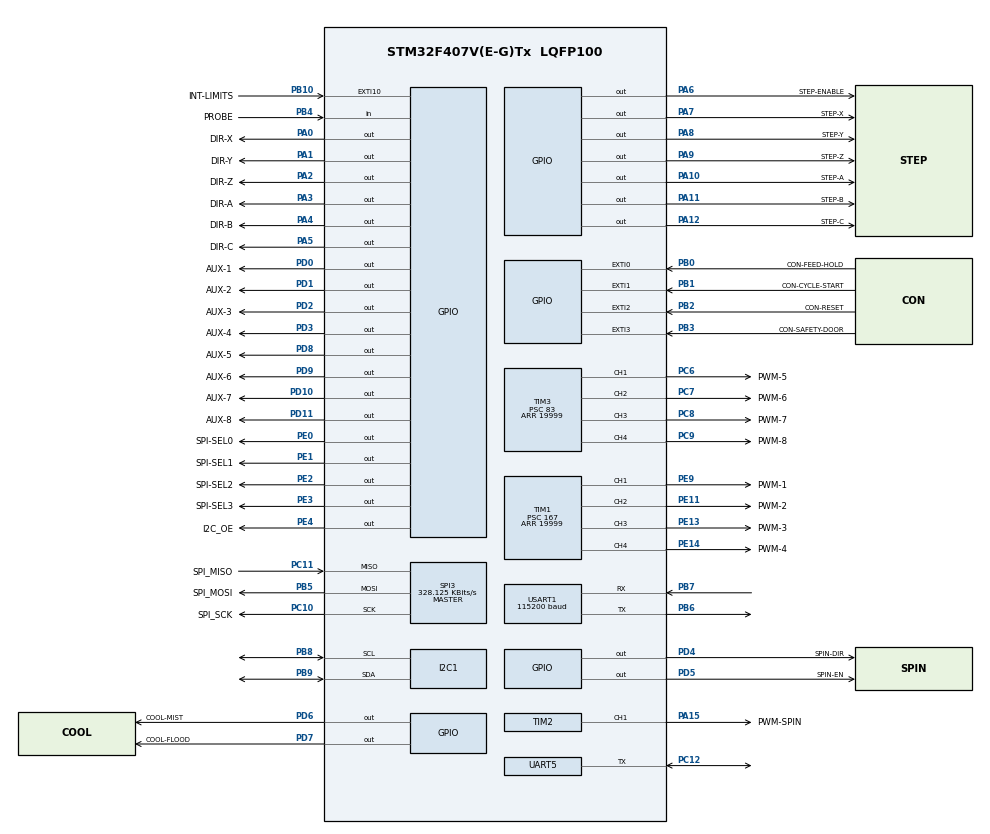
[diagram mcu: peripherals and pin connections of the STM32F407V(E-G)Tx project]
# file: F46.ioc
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Mcu.Family=STM32F4
Mcu.Name=STM32F407V(E-G)Tx
Mcu.Package=LQFP100
NVIC.EXTI0_IRQn=true\:0\:0\:false\:true\:true\:2\:true\:true\:true
NVIC.EXTI15_10_IRQn=true\:0\:0\:false\:false\:true\:true\:true\:true
NVIC.EXTI1_IRQn=true\:0\:0\:false\:true\:true\:3\:true\:true\:true
NVIC.EXTI2_IRQn=true\:0\:0\:false\:true\:true\:4\:true\:true\:true
NVIC.EXTI3_IRQn=true\:0\:0\:false\:true\:true\:5\:true\:true\:true
NVIC.PriorityGroup=NVIC_PRIORITYGROUP_4
NVIC.TIM5_IRQn=true\:0\:0\:false\:false\:true\:true\:true\:true
NVIC.TIM7_IRQn=true\:0\:0\:false\:false\:true\:true\:true\:true
NVIC.USART1_IRQn=true\:0\:0\:false\:true\:true\:1\:true\:true\:true
PA0-WKUP.GPIO_Label=DIR-X
PA0-WKUP.GPIO_ModeDefaultOutputPP=GPIO_MODE_OUTPUT_PP
PA0-WKUP.GPIO_Speed=GPIO_SPEED_FREQ_VERY_HIGH
PA0-WKUP.Signal=GPIO_Output
PA1.GPIO_Label=DIR-Y
PA1.GPIO_ModeDefaultOutputPP=GPIO_MODE_OUTPUT_PP
PA1.GPIO_Speed=GPIO_SPEED_FREQ_VERY_HIGH
PA1.Signal=GPIO_Output
PA10.GPIO_Label=STEP-A
PA10.GPIO_ModeDefaultOutputPP=GPIO_MODE_OUTPUT_PP
PA10.GPIO_Speed=GPIO_SPEED_FREQ_VERY_HIGH
PA10.Signal=GPIO_Output
PA11.GPIO_Label=STEP-B
PA11.GPIO_ModeDefaultOutputPP=GPIO_MODE_OUTPUT_PP
PA11.GPIO_Speed=GPIO_SPEED_FREQ_VERY_HIGH
PA11.Signal=GPIO_Output
PA12.GPIO_Label=STEP-C
PA12.GPIO_ModeDefaultOutputPP=GPIO_MODE_OUTPUT_PP
PA12.GPIO_Speed=GPIO_SPEED_FREQ_VERY_HIGH
PA12.Signal=GPIO_Output
PA13.Mode=Serial_Wire
PA13.Signal=SYS_JTMS-SWDIO
PA14.Mode=Serial_Wire
PA14.Signal=SYS_JTCK-SWCLK
PA15.GPIO_Label=PWM-SPIN
PA15.Signal=S_TIM2_CH1_ETR
PA2.GPIO_Label=DIR-Z
PA2.GPIO_ModeDefaultOutputPP=GPIO_MODE_OUTPUT_PP
PA2.GPIO_Speed=GPIO_SPEED_FREQ_VERY_HIGH
PA2.Signal=GPIO_Output
PA3.GPIO_Label=DIR-A
PA3.GPIO_ModeDefaultOutputPP=GPIO_MODE_OUTPUT_PP
PA3.GPIO_Speed=GPIO_SPEED_FREQ_VERY_HIGH
PA3.Signal=GPIO_Output
PA4.GPIO_Label=DIR-B
PA4.GPIO_ModeDefaultOutputPP=GPIO_MODE_OUTPUT_PP
PA4.GPIO_Speed=GPIO_SPEED_FREQ_VERY_HIGH
PA4.Signal=GPIO_Output
PA5.GPIO_Label=DIR-C
PA5.GPIO_ModeDefaultOutputPP=GPIO_MODE_OUTPUT_PP
PA5.GPIO_Speed=GPIO_SPEED_FREQ_VERY_HIGH
PA5.Signal=GPIO_Output
PA6.GPIO_Label=STEP-ENABLE
PA6.GPIO_ModeDefaultOutputPP=GPIO_MODE_OUTPUT_PP
PA6.GPIO_Speed=GPIO_SPEED_FREQ_VERY_HIGH
PA6.Signal=GPIO_Output
PA7.GPIO_Label=STEP-X
PA7.GPIO_ModeDefaultOutputPP=GPIO_MODE_OUTPUT_PP
PA7.GPIO_Speed=GPIO_SPEED_FREQ_VERY_HIGH
PA7.Signal=GPIO_Output
PA8.GPIO_Label=STEP-Y
PA8.GPIO_ModeDefaultOutputPP=GPIO_MODE_OUTPUT_PP
PA8.GPIO_Speed=GPIO_SPEED_FREQ_VERY_HIGH
PA8.Signal=GPIO_Output
PA9.GPIO_Label=STEP-Z
PA9.GPIO_ModeDefaultOutputPP=GPIO_MODE_OUTPUT_PP
PA9.GPIO_Speed=GPIO_SPEED_FREQ_VERY_HIGH
PA9.Signal=GPIO_Output
PB0.GPIO_Label=CON-FEED-HOLD
PB0.GPIO_ModeDefaultEXTI=GPIO_MODE_IT_FALLING
PB0.GPIO_PuPd=GPIO_PULLUP
PB0.Signal=GPXTI0
PB1.GPIO_Label=CON-CYCLE-START
PB1.GPIO_ModeDefaultEXTI=GPIO_MODE_IT_FALLING
PB1.GPIO_PuPd=GPIO_PULLUP
PB1.Signal=GPXTI1
PB10.GPIO_Label=INT-LIMITS
PB10.GPIO_ModeDefaultEXTI=GPIO_MODE_IT_FALLING
PB10.GPIO_PuPd=GPIO_PULLUP
PB10.Signal=GPXTI10
PB2.GPIO_Label=CON-RESET
PB2.GPIO_ModeDefaultEXTI=GPIO_MODE_IT_FALLING
PB2.GPIO_PuPd=GPIO_PULLUP
PB2.Signal=GPXTI2
PB3.GPIO_Label=CON-SAFETY-DOOR
PB3.GPIO_ModeDefaultEXTI=GPIO_MODE_IT_FALLING
PB3.GPIO_PuPd=GPIO_PULLUP
PB3.Signal=GPXTI3
PB4.GPIO_Label=PROBE
PB4.GPIO_PuPd=GPIO_PULLUP
PB4.Signal=GPIO_Input
PB5.GPIO_Label=SPI_MOSI
PB5.Mode=Full_Duplex_Master
PB5.Signal=SPI3_MOSI
PB6.Mode=Asynchronous
PB6.Signal=USART1_TX
PB7.Mode=Asynchronous
PB7.Signal=USART1_RX
PB8.GPIO_Pu=GPIO_PULLUP
PB8.Mode=I2C
PB8.Signal=I2C1_SCL
PB9.GPIO_Pu=GPIO_PULLUP
PB9.Mode=I2C
PB9.Signal=I2C1_SDA
PC10.GPIO_Label=SPI_SCK
PC10.Mode=Full_Duplex_Master
PC10.Signal=SPI3_SCK
PC11.GPIO_Label=SPI_MISO
PC11.Mode=Full_Duplex_Master
PC11.Signal=SPI3_MISO
PC12.Mode=Half_duplex(single_wire_mode)
PC12.Signal=UART5_TX
PC6.GPIO_Label=PWM-5
PC6.Signal=S_TIM3_CH1
PC7.GPIO_Label=PWM-6
PC7.Signal=S_TIM3_CH2
PC8.GPIO_Label=PWM-7
PC8.Signal=S_TIM3_CH3
PC9.GPIO_Label=PWM-8
PC9.Signal=S_TIM3_CH4
PD0.GPIO_Label=AUX-1
PD0.GPIO_ModeDefaultOutputPP=GPIO_MODE_OUTPUT_PP
PD0.GPIO_PuPd=GPIO_NOPULL
PD0.GPIO_Speed=GPIO_SPEED_FREQ_VERY_HIGH
PD0.PinState=GPIO_PIN_RESET
PD0.Signal=GPIO_Output
PD1.GPIO_Label=AUX-2
PD1.GPIO_ModeDefaultOutputPP=GPIO_MODE_OUTPUT_PP
PD1.GPIO_PuPd=GPIO_NOPULL
PD1.GPIO_Speed=GPIO_SPEED_FREQ_VERY_HIGH
PD1.PinState=GPIO_PIN_RESET
PD1.Signal=GPIO_Output
PD10.GPIO_Label=AUX-7
PD10.GPIO_ModeDefaultOutputPP=GPIO_MODE_OUTPUT_PP
PD10.GPIO_PuPd=GPIO_NOPULL
PD10.GPIO_Speed=GPIO_SPEED_FREQ_VERY_HIGH
PD10.PinState=GPIO_PIN_RESET
PD10.Signal=GPIO_Output
PD11.GPIO_Label=AUX-8
PD11.GPIO_ModeDefaultOutputPP=GPIO_MODE_OUTPUT_PP
PD11.GPIO_PuPd=GPIO_NOPULL
PD11.GPIO_Speed=GPIO_SPEED_FREQ_VERY_HIGH
PD11.PinState=GPIO_PIN_RESET
PD11.Signal=GPIO_Output
PD2.GPIO_Label=AUX-3
PD2.GPIO_Speed=GPIO_SPEED_FREQ_VERY_HIGH
PD2.Signal=GPIO_Output
PD3.GPIO_Label=AUX-4
PD3.GPIO_ModeDefaultOutputPP=GPIO_MODE_OUTPUT_PP
PD3.GPIO_PuPd=GPIO_NOPULL
PD3.GPIO_Speed=GPIO_SPEED_FREQ_VERY_HIGH
PD3.PinState=GPIO_PIN_RESET
PD3.Signal=GPIO_Output
PD4.GPIO_Label=SPIN-DIR
PD4.GPIO_ModeDefaultOutputPP=GPIO_MODE_OUTPUT_PP
PD4.GPIO_PuPd=GPIO_NOPULL
PD4.GPIO_Speed=GPIO_SPEED_FREQ_VERY_HIGH
PD4.PinState=GPIO_PIN_RESET
PD4.Signal=GPIO_Output
PD5.GPIO_Label=SPIN-EN
PD5.GPIO_ModeDefaultOutputPP=GPIO_MODE_OUTPUT_PP
PD5.GPIO_PuPd=GPIO_NOPULL
PD5.GPIO_Speed=GPIO_SPEED_FREQ_VERY_HIGH
PD5.PinState=GPIO_PIN_RESET
PD5.Signal=GPIO_Output
PD6.GPIO_Label=COOL-MIST
PD6.GPIO_ModeDefaultOutputPP=GPIO_MODE_OUTPUT_PP
PD6.GPIO_PuPd=GPIO_NOPULL
PD6.GPIO_Speed=GPIO_SPEED_FREQ_VERY_HIGH
PD6.PinState=GPIO_PIN_RESET
PD6.Signal=GPIO_Output
PD7.GPIO_Label=COOL-FLOOD
PD7.GPIO_ModeDefaultOutputPP=GPIO_MODE_OUTPUT_PP
PD7.GPIO_PuPd=GPIO_NOPULL
PD7.GPIO_Speed=GPIO_SPEED_FREQ_VERY_HIGH
PD7.PinState=GPIO_PIN_RESET
PD7.Signal=GPIO_Output
PD8.GPIO_Label=AUX-5
PD8.GPIO_ModeDefaultOutputPP=GPIO_MODE_OUTPUT_PP
PD8.GPIO_PuPd=GPIO_NOPULL
PD8.GPIO_Speed=GPIO_SPEED_FREQ_VERY_HIGH
PD8.PinState=GPIO_PIN_RESET
PD8.Signal=GPIO_Output
PD9.GPIO_Label=AUX-6
PD9.GPIO_ModeDefaultOutputPP=GPIO_MODE_OUTPUT_PP
PD9.GPIO_PuPd=GPIO_NOPULL
PD9.GPIO_Speed=GPIO_SPEED_FREQ_VERY_HIGH
PD9.PinState=GPIO_PIN_RESET
PD9.Signal=GPIO_Output
PE0.GPIO_Label=SPI-SEL0
PE0.GPIO_Speed=GPIO_SPEED_FREQ_VERY_HIGH
PE0.Signal=GPIO_Output
PE1.GPIO_Label=SPI-SEL1
PE1.GPIO_Speed=GPIO_SPEED_FREQ_VERY_HIGH
PE1.Signal=GPIO_Output
PE11.GPIO_Label=PWM-2
PE11.Signal=S_TIM1_CH2
PE13.GPIO_Label=PWM-3
PE13.Signal=S_TIM1_CH3
PE14.GPIO_Label=PWM-4
PE14.Signal=S_TIM1_CH4
PE2.GPIO_Label=SPI-SEL2
PE2.GPIO_Speed=GPIO_SPEED_FREQ_VERY_HIGH
PE2.Signal=GPIO_Output
PE3.GPIO_Label=SPI-SEL3
PE3.GPIO_Speed=GPIO_SPEED_FREQ_VERY_HIGH
PE3.Signal=GPIO_Output
PE4.GPIO_Label=I2C_OE
PE4.Signal=GPIO_Output
PE9.GPIO_Label=PWM-1
PE9.Signal=S_TIM1_CH1
PH0-OSC_IN.Mode=HSE-External-Oscillator
PH0-OSC_IN.Signal=RCC_OSC_IN
PH1-OSC_OUT.Mode=HSE-External-Oscillator
PH1-OSC_OUT.Signal=RCC_OSC_OUT
ProjectManager.HeapSize=0x200
ProjectManager.StackSize=0x400
ProjectManager.TargetToolchain=MDK-ARM V5.32
RCC.48MHZClocksFreq_Value=84000000
RCC.AHBFreq_Value=168000000
RCC.APB1CLKDivider=RCC_HCLK_DIV4
RCC.APB1Freq_Value=42000000
RCC.APB1TimFreq_Value=84000000
RCC.APB2CLKDivider=RCC_HCLK_DIV2
RCC.APB2Freq_Value=84000000
RCC.APB2TimFreq_Value=168000000
RCC.CortexFreq_Value=168000000
RCC.FLatency=FLASH_LATENCY_5
RCC.HCLKFreq_Value=168000000
RCC.HSE_VALUE=8000000
RCC.HSI_VALUE=16000000
RCC.LSE_VALUE=32768
RCC.PLLM=8
RCC.PLLN=168
RCC.SYSCLKFreq_VALUE=168000000
RCC.SYSCLKSource=RCC_SYSCLKSOURCE_PLLCLK
RCC.VCOOutputFreq_Value=336000000
SH.S_TIM1_CH1.0=TIM1_CH1,PWM Generation1 CH1
SH.S_TIM1_CH2.0=TIM1_CH2,PWM Generation2 CH2
SH.S_TIM1_CH3.0=TIM1_CH3,PWM Generation3 CH3
SH.S_TIM1_CH4.0=TIM1_CH4,PWM Generation4 CH4
SH.S_TIM2_CH1_ETR.0=TIM2_CH1,PWM Generation1 CH1
SH.S_TIM3_CH1.0=TIM3_CH1,PWM Generation1 CH1
SH.S_TIM3_CH2.0=TIM3_CH2,PWM Generation2 CH2
SH.S_TIM3_CH3.0=TIM3_CH3,PWM Generation3 CH3
SH.S_TIM3_CH4.0=TIM3_CH4,PWM Generation4 CH4
SPI3.BaudRatePrescaler=SPI_BAUDRATEPRESCALER_128
SPI3.CalculateBaudRate=328.125 KBits/s
SPI3.Direction=SPI_DIRECTION_2LINES
SPI3.Mode=SPI_MODE_MASTER
SPI3.VirtualType=VM_MASTER
TIM1.Channel-PWM\ Generation1\ CH1=TIM_CHANNEL_1
TIM1.Channel-PWM\ Generation2\ CH2=TIM_CHANNEL_2
TIM1.Channel-PWM\ Generation3\ CH3=TIM_CHANNEL_3
TIM1.Channel-PWM\ Generation4\ CH4=TIM_CHANNEL_4
TIM1.Period=19999
TIM1.Prescaler=167
TIM1.Pulse-PWM\ Generation1\ CH1=1499
TIM1.Pulse-PWM\ Generation2\ CH2=1499
TIM1.Pulse-PWM\ Generation3\ CH3=1499
TIM1.Pulse-PWM\ Generation4\ CH4=1499
TIM2.Channel-PWM\ Generation1\ CH1=TIM_CHANNEL_1
TIM2.Period=8399
TIM2.Prescaler=0
TIM3.Channel-PWM\ Generation1\ CH1=TIM_CHANNEL_1
TIM3.Channel-PWM\ Generation2\ CH2=TIM_CHANNEL_2
TIM3.Channel-PWM\ Generation3\ CH3=TIM_CHANNEL_3
TIM3.Channel-PWM\ Generation4\ CH4=TIM_CHANNEL_4
TIM3.Period=19999
TIM3.Prescaler=83
TIM3.Pulse-PWM\ Generation1\ CH1=1500
TIM3.Pulse-PWM\ Generation2\ CH2=1500
TIM3.Pulse-PWM\ Generation3\ CH3=1500
TIM3.Pulse-PWM\ Generation4\ CH4=1500
TIM5.Period=0
TIM5.Prescaler=0
UART5.VirtualMode=Asynchronous
USART1.BaudRate=115200
USART1.VirtualMode=VM_ASYNC
VP_TIM1_VS_ClockSourceINT.Mode=Internal
VP_TIM2_VS_ClockSourceINT.Mode=Internal
VP_TIM3_VS_ClockSourceINT.Mode=Internal
VP_TIM5_VS_ClockSourceINT.Mode=Internal
VP_TIM7_VS_ClockSourceINT.Mode=Enable_Timer
board=F407VEG6

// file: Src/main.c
/* USER CODE BEGIN Header */
/**
  ******************************************************************************
  * @file           : main.c
  * @brief          : Main program body
  ******************************************************************************
  * @attention
  *
  * <h2><center>&copy; Copyright (c) 2019 STMicroelectronics.
  * All rights reserved.</center></h2>
  *
  * Copyright (c) 2018-2019 Thomas Truong
  *
  *
  * This software component is licensed by ST under BSD 3-Clause license,
  * the "License"; You may not use this file except in compliance with the
  * License. You may obtain a copy of the License at:
  *                        opensource.org/licenses/BSD-3-Clause
  *
  ******************************************************************************
  */
/* USER CODE END Header */
#include "main.h"
#include "i2c.h"
#include "spi.h"
#include "tim.h"
#include "usart.h"
#include "gpio.h"

/* USER CODE BEGIN Includes */
#include "grbl.h"
/* USER CODE END Includes */

/* USER CODE BEGIN PV */
/* Private variables ---------------------------------------------------------*/
// Declare system global variable structure
system_t sys;
int32_t sys_position[N_AXIS];      // Real-time machine (aka home) position vector in steps.
int32_t sys_probe_position[N_AXIS]; // Last probe position in machine coordinates and steps.
volatile uint8_t sys_probe_state;   // Probing state value.  Used to coordinate the probing cycle with stepper ISR.
volatile uint8_t sys_rt_exec_state;   // Global realtime executor bitflag variable for state management. See EXEC bitmasks.
volatile uint8_t sys_rt_exec_alarm;   // Global realtime executor bitflag variable for setting various alarms.
volatile uint8_t sys_rt_exec_motion_override; // Global realtime executor bitflag variable for motion-based overrides.
volatile uint8_t sys_rt_exec_accessory_override; // Global realtime executor bitflag variable for spindle/coolant overrides.
#ifdef DEBUG
  volatile uint8_t sys_rt_exec_debug;
#endif

char pHelloVE[] = "Hello G6F1VE\r\n";

/* USER CODE END PV */

void SystemClock_Config(void);
static void MX_NVIC_Init(void);

int main(void)
{

  /* MCU Configuration--------------------------------------------------------*/

  /* Reset of all peripherals, Initializes the Flash interface and the Systick. */
  HAL_Init();

  /* Configure the system clock */
  SystemClock_Config();

  /* Initialize all configured peripherals */
  MX_GPIO_Init();
  MX_TIM3_Init();
  MX_TIM1_Init();
  MX_TIM2_Init();
  MX_USART1_UART_Init();
  MX_TIM5_Init();
  MX_I2C1_Init();
  MX_SPI3_Init();
  MX_UART5_Init();
  MX_TIM7_Init();

  /* Initialize interrupts */
  MX_NVIC_Init();
  /* USER CODE BEGIN 2 */
  timing_init();
  uart_init();
  eeprom_init();
  serial_init();   // Setup serial baud rate and interrupts
  settings_init(); // Load Grbl settings from EEPROM
  stepper_init();  // Configure stepper pins and interrupt timers
  system_init();   // Configure pinout pins and pin-change interrupt
  memset(sys_position,0,sizeof(sys_position)); // Clear machine position.

  // Initialize system state.
  #ifdef FORCE_INITIALIZATION_ALARM
    // Force Grbl into an ALARM state upon a power-cycle or hard reset.
    sys.state = STATE_ALARM;
  #else
    sys.state = STATE_IDLE;
  #endif

  // Check for power-up and set system alarm if homing is enabled to force homing cycle
  // by setting Grbl's alarm state. Alarm locks out all g-code commands, including the
  // startup scripts, but allows access to settings and internal commands. Only a homing
  // cycle '$H' or kill alarm locks '$X' will disable the alarm.
  // NOTE: The startup script will run after successful completion of the homing cycle, but
  // not after disabling the alarm locks. Prevents motion startup blocks from crashing into
  // things uncontrollably. Very bad.
  #ifdef HOMING_INIT_LOCK
    if (bit_istrue(settings.flags,BITFLAG_HOMING_ENABLE)) { sys.state = STATE_ALARM; }
  #endif

  /* USER CODE END 2 */

  /* Infinite loop */
  /* USER CODE BEGIN WHILE */
  while (1)
  {
		// Reset system variables.
		uint8_t prior_state = sys.state;
		memset(&sys, 0, sizeof(system_t)); // Clear system struct variable.
		sys.state = prior_state;
		sys.f_override = DEFAULT_FEED_OVERRIDE;  // Set to 100%
		sys.r_override = DEFAULT_RAPID_OVERRIDE; // Set to 100%
		sys.spindle_speed_ovr = DEFAULT_SPINDLE_SPEED_OVERRIDE; // Set to 100%
			memset(sys_probe_position,0,sizeof(sys_probe_position)); // Clear probe position.
		sys_probe_state = 0;
		sys_rt_exec_state = 0;
		sys_rt_exec_alarm = 0;
		sys_rt_exec_motion_override = 0;
		sys_rt_exec_accessory_override = 0;

		// Reset Grbl primary systems.
		serial_reset_read_buffer(); // Clear serial read buffer
		gc_init(); // Set g-code parser to default state
		spindle_init();
		coolant_init();
		spi_limits_init();				//-- expansion io based limits, before limits_init()
		limits_init();

		probe_init();
		inoutputs_init();

		plan_reset(); // Clear block buffer and planner variables
		st_reset(); // Clear stepper subsystem variables.

		// Sync cleared gcode and planner positions to current system position.
		plan_sync_position();
		gc_sync_position();

		// Print welcome message. Indicates an initialization has occured at power-up or with a reset.
		report_init_message();

		// Start Grbl main loop. Processes program inputs and executes them.
		protocol_main_loop();

    /* USER CODE END WHILE */

  }
}

void SystemClock_Config(void)
{
  RCC_OscInitTypeDef RCC_OscInitStruct = {0};
  RCC_ClkInitTypeDef RCC_ClkInitStruct = {0};

  /** Configure the main internal regulator output voltage
  */
  __HAL_RCC_PWR_CLK_ENABLE();
  __HAL_PWR_VOLTAGESCALING_CONFIG(PWR_REGULATOR_VOLTAGE_SCALE1);

  /** Initializes the RCC Oscillators according to the specified parameters
  * in the RCC_OscInitTypeDef structure.
  */
  RCC_OscInitStruct.OscillatorType = RCC_OSCILLATORTYPE_HSE;
  RCC_OscInitStruct.HSEState = RCC_HSE_ON;
  RCC_OscInitStruct.PLL.PLLState = RCC_PLL_ON;
  RCC_OscInitStruct.PLL.PLLSource = RCC_PLLSOURCE_HSE;
  RCC_OscInitStruct.PLL.PLLM = 6;
  RCC_OscInitStruct.PLL.PLLN = 168;
  RCC_OscInitStruct.PLL.PLLP = RCC_PLLP_DIV2;
  RCC_OscInitStruct.PLL.PLLQ = 4;
  if (HAL_RCC_OscConfig(&RCC_OscInitStruct) != HAL_OK)
  {
    Error_Handler();
  }

  /** Initializes the CPU, AHB and APB buses clocks
  */
  RCC_ClkInitStruct.ClockType = RCC_CLOCKTYPE_HCLK|RCC_CLOCKTYPE_SYSCLK
                              |RCC_CLOCKTYPE_PCLK1|RCC_CLOCKTYPE_PCLK2;
  RCC_ClkInitStruct.SYSCLKSource = RCC_SYSCLKSOURCE_PLLCLK;
  RCC_ClkInitStruct.AHBCLKDivider = RCC_SYSCLK_DIV1;
  RCC_ClkInitStruct.APB1CLKDivider = RCC_HCLK_DIV4;
  RCC_ClkInitStruct.APB2CLKDivider = RCC_HCLK_DIV2;

  if (HAL_RCC_ClockConfig(&RCC_ClkInitStruct, FLASH_LATENCY_5) != HAL_OK)
  {
    Error_Handler();
  }
}

/**
  * @brief NVIC Configuration.
  * @retval None
  */
static void MX_NVIC_Init(void)
{
  /* USART1_IRQn interrupt configuration */
  NVIC_SetPriority(USART1_IRQn, NVIC_EncodePriority(NVIC_GetPriorityGrouping(),0, 0));
  NVIC_EnableIRQ(USART1_IRQn);
  /* EXTI0_IRQn interrupt configuration */
  HAL_NVIC_SetPriority(EXTI0_IRQn, 0, 0);
  HAL_NVIC_EnableIRQ(EXTI0_IRQn);
  /* EXTI1_IRQn interrupt configuration */
  HAL_NVIC_SetPriority(EXTI1_IRQn, 0, 0);
  HAL_NVIC_EnableIRQ(EXTI1_IRQn);
  /* EXTI2_IRQn interrupt configuration */
  HAL_NVIC_SetPriority(EXTI2_IRQn, 0, 0);
  HAL_NVIC_EnableIRQ(EXTI2_IRQn);
  /* EXTI3_IRQn interrupt configuration */
  HAL_NVIC_SetPriority(EXTI3_IRQn, 0, 0);
  HAL_NVIC_EnableIRQ(EXTI3_IRQn);
}

/* USER CODE BEGIN 4 */

void Analog_Timer_Init()
{
		LL_TIM_CC_EnableChannel(ANA1_TIMER,ANA1_CHANNEL);
		LL_TIM_CC_EnableChannel(ANA2_TIMER,ANA2_CHANNEL);
		LL_TIM_CC_EnableChannel(ANA3_TIMER,ANA3_CHANNEL);
		LL_TIM_CC_EnableChannel(ANA4_TIMER,ANA4_CHANNEL);
		//LL_TIM_DisableAllOutputs(ANA1_TIMER); //-- same for 1..4
		LL_TIM_EnableAllOutputs(ANA1_TIMER);
		LL_TIM_EnableCounter(ANA1_TIMER);
		//-- start timer with PWM disabled

		LL_TIM_CC_EnableChannel(ANA5_TIMER,ANA5_CHANNEL);
		LL_TIM_CC_EnableChannel(ANA6_TIMER,ANA6_CHANNEL);
		LL_TIM_CC_EnableChannel(ANA7_TIMER,ANA7_CHANNEL);
		LL_TIM_CC_EnableChannel(ANA8_TIMER,ANA8_CHANNEL);
//		LL_TIM_DisableAllOutputs(ANA5_TIMER); //-- same for 5..8
		LL_TIM_EnableAllOutputs(ANA5_TIMER); //-- same for 5..8
		LL_TIM_EnableCounter(ANA5_TIMER);
		//-- start timer with PWM disabled

}
/* USER CODE END 4 */

void Error_Handler(void)
{
}
